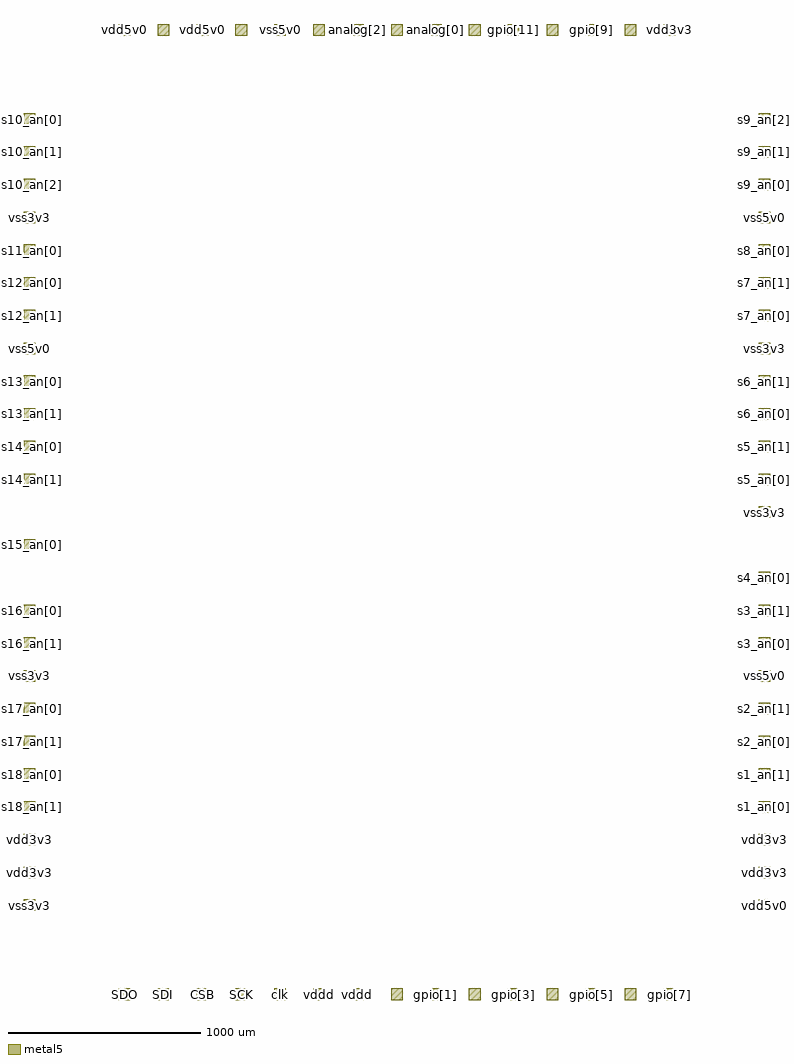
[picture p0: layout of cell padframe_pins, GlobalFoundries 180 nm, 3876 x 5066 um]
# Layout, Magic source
magic
tech gf180mcuD
<< metal5 >>
rect 9910 100160 11110 101360
rect 13950 100160 15150 101360
rect 17990 100160 19190 101360
rect 22030 100160 23230 101360
rect 26070 100160 27270 101360
rect 30110 100160 31310 101360
rect 34150 100160 35350 101360
rect 38190 100160 39390 101360
rect 42230 100160 43430 101360
rect 46270 100160 47470 101360
rect 50310 100160 51510 101360
rect 54350 100160 55550 101360
rect 58390 100160 59590 101360
rect 62430 100160 63630 101360
rect 66470 100160 67670 101360
rect 40 90890 1240 92090
rect 76360 90890 77560 92090
rect 40 87490 1240 88690
rect 76360 87490 77560 88690
rect 40 84090 1240 85290
rect 76360 84090 77560 85290
rect 40 80690 1240 81890
rect 76360 80690 77560 81890
rect 40 77290 1240 78490
rect 76360 77290 77560 78490
rect 40 73890 1240 75090
rect 76360 73890 77560 75090
rect 40 70490 1240 71690
rect 76360 70490 77560 71690
rect 40 67090 1240 68290
rect 76360 67090 77560 68290
rect 40 63690 1240 64890
rect 76360 63690 77560 64890
rect 40 60290 1240 61490
rect 76360 60290 77560 61490
rect 40 56890 1240 58090
rect 76360 56890 77560 58090
rect 40 53490 1240 54690
rect 76360 53490 77560 54690
rect 76360 50090 77560 51290
rect 40 46690 1240 47890
rect 76360 43290 77560 44490
rect 40 39890 1240 41090
rect 76360 39890 77560 41090
rect 40 36490 1240 37690
rect 76360 36490 77560 37690
rect 40 33090 1240 34290
rect 76360 33090 77560 34290
rect 40 29690 1240 30890
rect 76360 29690 77560 30890
rect 40 26290 1240 27490
rect 76360 26290 77560 27490
rect 40 22890 1240 24090
rect 76360 22890 77560 24090
rect 40 19490 1240 20690
rect 76360 19490 77560 20690
rect 40 16090 1240 17290
rect 76360 16090 77560 17290
rect 40 12690 1240 13890
rect 76360 12690 77560 13890
rect 40 9290 1240 10490
rect 76360 9290 77560 10490
rect 9910 40 11110 1240
rect 13950 40 15150 1240
rect 17990 40 19190 1240
rect 22030 40 23230 1240
rect 26070 40 27270 1240
rect 30110 40 31310 1240
rect 34150 40 35350 1240
rect 38190 40 39390 1240
rect 42230 40 43430 1240
rect 46270 40 47470 1240
rect 50310 40 51510 1240
rect 54350 40 55550 1240
rect 58390 40 59590 1240
rect 62430 40 63630 1240
rect 66470 40 67670 1240
<< labels >>
flabel metal5 9910 40 11110 1240 0 FreeSans 3200 0 0 0 SDO
port 1 nsew
flabel metal5 13950 40 15150 1240 0 FreeSans 3200 0 0 0 SDI
port 2 nsew
flabel metal5 17990 40 19190 1240 0 FreeSans 3200 0 0 0 CSB
port 3 nsew
flabel metal5 22030 40 23230 1240 0 FreeSans 3200 0 0 0 SCK
port 4 nsew
flabel metal5 26070 40 27270 1240 0 FreeSans 3200 0 0 0 clk
port 5 nsew
flabel metal5 30110 40 31310 1240 0 FreeSans 3200 0 0 0 vddd
port 6 nsew
flabel metal5 34150 40 35350 1240 0 FreeSans 3200 0 0 0 vddd
port 6 nsew
flabel metal5 38190 40 39390 1240 0 FreeSans 3200 0 0 0 gpio[0]
port 7 nsew
flabel metal5 42230 40 43430 1240 0 FreeSans 3200 0 0 0 gpio[1]
port 8 nsew
flabel metal5 46270 40 47470 1240 0 FreeSans 3200 0 0 0 gpio[2]
port 9 nsew
flabel metal5 50310 40 51510 1240 0 FreeSans 3200 0 0 0 gpio[3]
port 10 nsew
flabel metal5 54350 40 55550 1240 0 FreeSans 3200 0 0 0 gpio[4]
port 11 nsew
flabel metal5 58390 40 59590 1240 0 FreeSans 3200 0 0 0 gpio[5]
port 12 nsew
flabel metal5 62430 40 63630 1240 0 FreeSans 3200 0 0 0 gpio[6]
port 13 nsew
flabel metal5 66470 40 67670 1240 0 FreeSans 3200 0 0 0 gpio[7]
port 14 nsew
flabel metal5 40 90890 1240 92090 0 FreeSans 3200 0 0 0 s10_an[0]
port 45 nsew
flabel metal5 40 87490 1240 88690 0 FreeSans 3200 0 0 0 s10_an[1]
port 46 nsew
flabel metal5 40 84090 1240 85290 0 FreeSans 3200 0 0 0 s10_an[2]
port 47 nsew
flabel metal5 40 80690 1240 81890 0 FreeSans 3200 0 0 0 vss3v3
port 25 nsew
flabel metal5 40 77290 1240 78490 0 FreeSans 3200 0 0 0 s11_an[0]
port 48 nsew
flabel metal5 40 73890 1240 75090 0 FreeSans 3200 0 0 0 s12_an[0]
port 49 nsew
flabel metal5 40 70490 1240 71690 0 FreeSans 3200 0 0 0 s12_an[1]
port 50 nsew
flabel metal5 40 63690 1240 64890 0 FreeSans 3200 0 0 0 s13_an[0]
port 51 nsew
flabel metal5 40 60290 1240 61490 0 FreeSans 3200 0 0 0 s13_an[1]
port 52 nsew
flabel metal5 40 56890 1240 58090 0 FreeSans 3200 0 0 0 s14_an[0]
port 53 nsew
flabel metal5 40 53490 1240 54690 0 FreeSans 3200 0 0 0 s14_an[1]
port 54 nsew
flabel metal5 40 53490 1240 54690 0 FreeSans 3200 0 0 0 s14_an[2]
port 55 nsew
flabel metal5 40 67090 1240 68290 0 FreeSans 3200 0 0 0 vss5v0
port 21 nsew
flabel metal5 40 46690 1240 47890 0 FreeSans 3200 0 0 0 s15_an[0]
port 56 nsew
flabel metal5 40 39890 1240 41090 0 FreeSans 3200 0 0 0 s16_an[0]
port 57 nsew
flabel metal5 40 36490 1240 37690 0 FreeSans 3200 0 0 0 s16_an[1]
port 58 nsew
flabel metal5 40 33090 1240 34290 0 FreeSans 3200 0 0 0 vss3v3
port 25 nsew
flabel metal5 40 29690 1240 30890 0 FreeSans 3200 0 0 0 s17_an[0]
port 59 nsew
flabel metal5 40 26290 1240 27490 0 FreeSans 3200 0 0 0 s17_an[1]
port 60 nsew
flabel metal5 40 22890 1240 24090 0 FreeSans 3200 0 0 0 s18_an[0]
port 61 nsew
flabel metal5 40 19490 1240 20690 0 FreeSans 3200 0 0 0 s18_an[1]
port 62 nsew
flabel metal5 40 16090 1240 17290 0 FreeSans 3200 0 0 0 vdd3v3
port 16 nsew
flabel metal5 40 12690 1240 13890 0 FreeSans 3200 0 0 0 vdd3v3
port 16 nsew
flabel metal5 40 9290 1240 10490 0 FreeSans 3200 0 0 0 vss3v3
port 25 nsew
flabel metal5 66470 100160 67670 101360 0 FreeSans 3200 0 0 0 vdd3v3
port 16 nsew
flabel metal5 62430 100160 63630 101360 0 FreeSans 3200 0 0 0 gpio[8]
port 37 nsew
flabel metal5 58390 100160 59590 101360 0 FreeSans 3200 0 0 0 gpio[9]
port 38 nsew
flabel metal5 54350 100160 55550 101360 0 FreeSans 3200 0 0 0 gpio[10]
port 39 nsew
flabel metal5 50310 100160 51510 101360 0 FreeSans 3200 0 0 0 gpio[11]
port 40 nsew
flabel metal5 46270 100160 47470 101360 0 FreeSans 3200 0 0 0 vss5v0
port 21 nsew
flabel metal5 42230 100160 43430 101360 0 FreeSans 3200 0 0 0 analog[0]
port 41 nsew
flabel metal5 38190 100160 39390 101360 0 FreeSans 3200 0 0 0 analog[1]
port 42 nsew
flabel metal5 34150 100160 35350 101360 0 FreeSans 3200 0 0 0 analog[2]
port 43 nsew
flabel metal5 30110 100160 31310 101360 0 FreeSans 3200 0 0 0 analog[3]
port 44 nsew
flabel metal5 26070 100160 27270 101360 0 FreeSans 3200 0 0 0 vss5v0
port 21 nsew
flabel metal5 22030 100160 23230 101360 0 FreeSans 3200 0 0 0 vdd5v0
port 15 nsew
flabel metal5 17990 100160 19190 101360 0 FreeSans 3200 0 0 0 vdd5v0
port 15 nsew
flabel metal5 13950 100160 15150 101360 0 FreeSans 3200 0 0 0 vdd5v0
port 15 nsew
flabel metal5 9910 100160 11110 101360 0 FreeSans 3200 0 0 0 vdd5v0
port 15 nsew
flabel metal5 76360 9290 77560 10490 0 FreeSans 3200 0 0 0 vdd5v0
port 15 nsew
flabel metal5 76360 12690 77560 13890 0 FreeSans 3200 0 0 0 vdd3v3
port 16 nsew
flabel metal5 76360 16090 77560 17290 0 FreeSans 3200 0 0 0 vdd3v3
port 16 nsew
flabel metal5 76360 19490 77560 20690 0 FreeSans 3200 0 0 0 s1_an[0]
port 17 nsew
flabel metal5 76360 22890 77560 24090 0 FreeSans 3200 0 0 0 s1_an[1]
port 18 nsew
flabel metal5 76360 26290 77560 27490 0 FreeSans 3200 0 0 0 s2_an[0]
port 19 nsew
flabel metal5 76360 29690 77560 30890 0 FreeSans 3200 0 0 0 s2_an[1]
port 20 nsew
flabel metal5 76360 33090 77560 34290 0 FreeSans 3200 0 0 0 vss5v0
port 21 nsew
flabel metal5 76360 36490 77560 37690 0 FreeSans 3200 0 0 0 s3_an[0]
port 22 nsew
flabel metal5 76360 39890 77560 41090 0 FreeSans 3200 0 0 0 s3_an[1]
port 23 nsew
flabel metal5 76360 43290 77560 44490 0 FreeSans 3200 0 0 0 s4_an[0]
port 24 nsew
flabel metal5 76360 50090 77560 51290 0 FreeSans 3200 0 0 0 vss3v3
port 25 nsew
flabel metal5 76360 53490 77560 54690 0 FreeSans 3200 0 0 0 s5_an[0]
port 26 nsew
flabel metal5 76360 56890 77560 58090 0 FreeSans 3200 0 0 0 s5_an[1]
port 27 nsew
flabel metal5 76360 56890 77560 58090 0 FreeSans 3200 0 0 0 s5_an[2]
port 28 nsew
flabel metal5 76360 60290 77560 61490 0 FreeSans 3200 0 0 0 s6_an[0]
port 29 nsew
flabel metal5 76360 63690 77560 64890 0 FreeSans 3200 0 0 0 s6_an[1]
port 30 nsew
flabel metal5 76360 67090 77560 68290 0 FreeSans 3200 0 0 0 vss3v3
port 25 nsew
flabel metal5 76360 70490 77560 71690 0 FreeSans 3200 0 0 0 s7_an[0]
port 31 nsew
flabel metal5 76360 73890 77560 75090 0 FreeSans 3200 0 0 0 s7_an[1]
port 32 nsew
flabel metal5 76360 77290 77560 78490 0 FreeSans 3200 0 0 0 s8_an[0]
port 33 nsew
flabel metal5 76360 80690 77560 81890 0 FreeSans 3200 0 0 0 vss5v0
port 21 nsew
flabel metal5 76360 84090 77560 85290 0 FreeSans 3200 0 0 0 s9_an[0]
port 34 nsew
flabel metal5 76360 87490 77560 88690 0 FreeSans 3200 0 0 0 s9_an[1]
port 35 nsew
flabel metal5 76360 90890 77560 92090 0 FreeSans 3200 0 0 0 s9_an[2]
port 36 nsew
<< end >>
